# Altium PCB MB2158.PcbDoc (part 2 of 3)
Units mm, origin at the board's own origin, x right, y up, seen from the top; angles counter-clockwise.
Board outline 43 x 60 mm, 4 copper layers (Top Layer, Signal Layer 1, Signal Layer 2, Bottom Layer), stack 1.539 mm thick; 118 components, 89 nets, 427 pads, 825 vias.

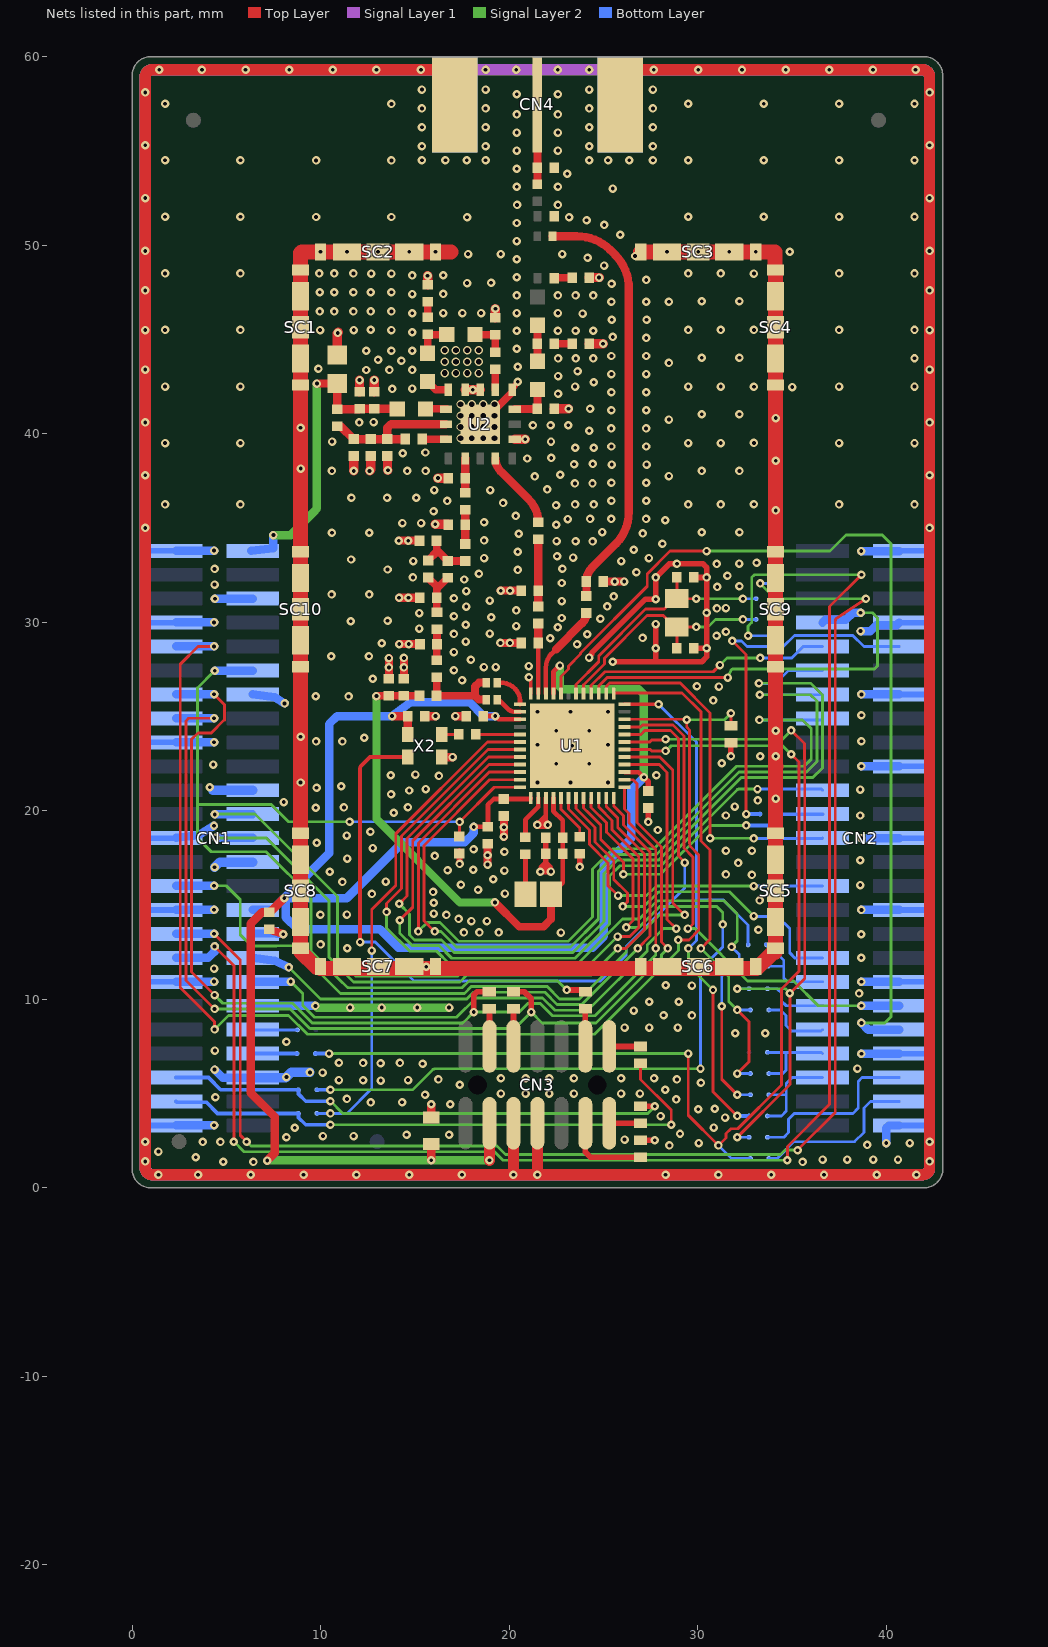
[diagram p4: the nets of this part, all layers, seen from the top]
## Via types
v1: diameter 0.45, hole 0.2, Top Layer to Bottom Layer, tented both sides, 797 vias
v2: diameter 0.45, hole 0.3, Top Layer to Bottom Layer, tented both sides, 28 vias

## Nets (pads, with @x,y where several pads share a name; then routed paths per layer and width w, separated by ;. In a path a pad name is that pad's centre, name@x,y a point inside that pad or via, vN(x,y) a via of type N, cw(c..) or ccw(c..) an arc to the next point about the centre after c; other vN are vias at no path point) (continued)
GND: C1.1 C2.1 C4.1 C7.1 C8.1 C9.1 C10.1 C11.1 C12.1 C13.1 C14.2 C15.1 C16.1 C17.1 C18.1 C19.1 C20.1 C21.1 C22.1 C23.2 C24.1 C26.1 C27.2 C28.2 C29.2 C30.2 C31.2 C34.1 C35.1 C37.1 C39.2 C40.1 CN1.1 CN1.6 CN1.7 CN1.14 CN1.17 CN1.22 CN1.25 CN1.28 CN1.31 CN1.34 CN1.37 CN1.40 CN1.46 CN1.49 CN2.2 CN2.8 CN2.14 CN2.20 CN2.26 CN2.32 CN2.38 CN2.44 CN2.50 CN3.5 CN3.7 CN4.2 CN4.3 CN4.4 CN4.5 L3.2 L12.2 L17.2 L19.2 R2.1 R8.1 SC1.1 SC2.1 SC3.1 SC4.1 SC5.1 SC6.1 SC7.1 SC8.1 SC9.1 SC10.1 U1.24 U1.39 U1.49 U2.6 U2.9 U2.11 U2.12 U2.17 X2.2 | length 1058.1
  Top Layer w0.2: v1(21.05,27.08) 21.05,27.013 21.15,26.913 U1.24@21.15,26.225
  Top Layer w0.25: v1@21.538,19.288 v1(21.5,19.25) 21.5,19.275 21.95,19.725 ; U1.39@21.95,20.675 21.95,19.725 ; v1(22.05,19.25) 21.95,19.35 21.95,19.725
  Top Layer w0.3: v1(17.37,17.179) C20.1@17.37,17.884 ; U2.17@18.9,41.154 U2.17@19.124,41.154 ; U2.9@20.148,42.178 20.202,42.178 20.175,42.205 U2.9@20.175,42.33 v1(20.453,42.759) ; C22.1@21.941,18.572 C23.2@21.941,17.722 21.941,17.235 ; v1@22.221,16.772 21.941,16.772 ; v1(22.221,16.778) 22.192,16.807 22.192,16.913 22.187,16.918 22.187,16.989 21.941,17.235 ; v1(23.75,17.02) C21.1@23.75,17.725 ; v1(24.243,28.128) 24.243,28.168 24.375,28.301 24.375,28.366 27.234,31.225 v1(27.775,31.225) v1(27.775,32.375) 28.5,33.1 v1(28.9,33.1) 30.275,33.1 30.475,32.9 v1(30.475,32.375) ; v1(25.5,27.9) 27.7,27.9 ; R8.1@26.975,2.525 v1(27.725,2.525) ; v1(27.375,19.411) C17.1@27.375,20.15 ; v1(27.775,29.9) v1(27.775,28.625) 27.775,27.975 27.7,27.9 ; C13.1@29.8,28.625 v1(30.475,28.625) ; C9.1@29.8,32.375 v1(30.475,32.375) ; v1(31.763,22.895) R2.1@31.763,23.6 ; 21.941,16.772 21.941,17.235 ; 21.941,16.772 v1(21.662,16.772) 21.69,16.801 21.69,16.907 21.695,16.912 21.695,16.995 21.935,17.235 21.941,17.235 ; 27.7,27.9 30.214,27.9 30.475,28.161 v1(30.475,28.625) ; v1(30.475,28.625) v1(30.475,30.5) v1(30.475,32.375)
  Top Layer w0.4: U2.17@19.124,41.154 U2.9@20.148,42.178
  Top Layer w0.43: C14.2@13.625,27 v1(13.625,27.6) v1(13.625,28.1) ; v1(14.15,34.325) v1(14.649,34.325) C4.1@15.25,34.325 ; v1(14.161,31.3) v1(14.661,31.3) C8.1@15.261,31.3 ; v1(14.175,28.841) v1(14.675,28.841) C11.1@15.174,28.841 ; C15.1@14.42,27.005 v1(14.42,27.605) v1(14.42,28.105) ; v1(18.857,17.146) v1(18.857,17.646) C18.1@18.857,18.246 ; v1(19.54,28.9) v1(20.04,28.9) C12.1@20.64,28.9 ; v1(19.55,31.675) v1(20.05,31.675) C10.1@20.65,31.675 ; v1(19.725,18.625) v1(19.725,19.125) C19.1@19.725,19.725 ; L3.2@25,32.16 v1(25.6,32.16) v1(26.1,32.16)
  Top Layer w0.45: C24.1@7.286,13.715 7.341,13.685 v1(8.021,13.455) ; C7.1@15.527,25.025 v1(16.102,25.025) ; C26.1@15.875,3.725 v1(15.875,4.43) ; X2.2@16.427,22.85 v1(17.002,22.85) ; v1(17.15,25.025) C16.1@17.725,25.025 ; v1(21.5,19.25) v1(22.05,19.25)
  Top Layer w0.5: C27.2@10.881,44.175 10.881,45.316 v1@10.944,45.379 ; v1(11.759,38.027) 11.77,38.038 C39.2@11.77,38.817 ; v1(12.066,42.847) 12.066,42.219 C31.2@12.068,42.217 ; v1(12.6,38.027) 12.659,38.086 C28.2@12.659,38.817 ; v1(12.842,42.847) 12.842,42.22 C29.2@12.844,42.217 ; C30.2@13.548,38.817 13.548,38.091 v1(13.572,38.066) ; v1(15.671,48.38) 15.671,48.377 15.675,48.373 L12.2@15.675,47.9 ; v1(16.079,35.192) 16.77,35.192 16.775,35.187 C40.1@16.775,35.173 ; v1(16.224,37.643) C37.1@16.775,37.643 ; U2.12@17.675,42.33 U2.11@18.475,42.33 ; v1(19.273,46.63) 19.273,46.152 C34.1@19.275,46.15 ; U2.6@20.3,39.705 v1(20.85,39.705) ; C35.1@22.4,41.322 v1(23.15,41.322) ; L17.2@24.25,44.768 v1(24.983,44.768) ; L19.2@24.25,48.282 v1(24.771,48.282)
  Top Layer w0.6: CN4.3@17.119,57.46 17.119,58.394 16.212,59.3 1.075,59.3 ccw(c1.075,58.925) 0.7,58.925 v1(0.7,43.4) v1(0.7,40.6) v1(0.7,37.8) v1(0.7,35) v1(0.7,2.45) 0.7,1.075 ccw(c1.075,1.075) 1.075,0.7 41.925,0.7 ; v1(20.225,0.7) 20.23,0.705 CN3.5@20.23,3.43 ; v1(21.5,0.7) CN3.7@21.5,3.43 ; CN4.2@25.881,57.46 25.881,58.394 26.787,59.3 41.925,59.3 cw(c41.925,58.925) 42.3,58.925 v1(42.3,35) v1(42.3,2.45) 42.3,1.075 ; 41.925,0.7 ccw(c41.925,1.075) 42.3,1.075 ; 41.925,0.7 ccw(c41.925,1.075) 42.3,1.075
  Top Layer w0.8: SC1.1@8.939,48.686 8.939,49.582 9.002,49.645 v1(9.998,49.645) v1(11.398,49.645) v1(13.048,49.645) v1(14.698,49.645) v1(16.098,49.645) 16.921,49.645 ; SC8.1@8.989,14.353 8.989,14.038 SC8.1@8.939,13.988 ; SC8.1@8.989,15.588 SC8.1@8.939,15.638 ; SC1.1@8.989,48.619 8.939,48.569 SC1.1@8.939,47.286 SC1.1@8.939,45.636 SC1.1@8.939,43.986 SC1.1@8.939,42.586 8.939,42.469 8.939,33.629 8.939,24.644 8.939,19.488 8.939,18.688 SC8.1@8.939,15.638 ; SC3.1@26.979,49.645 v1(28.379,49.645) v1(30.029,49.645) v1(31.679,49.645) v1(33.079,49.645) 34.111,49.645 34.111,48.714 SC4.1@34.139,48.686 SC4.1@34.139,47.286 SC4.1@34.139,45.636 SC4.1@34.139,43.986 SC4.1@34.139,42.586 v1(34.139,40.826) v1(34.139,38.562) v1(34.139,35.927) SC9.1@34.139,33.745 SC9.1@34.139,32.345 SC9.1@34.139,30.695 SC9.1@34.139,29.045 SC9.1@34.139,27.645 v1(34.139,24.25) 34.139,22.341 ; 34.156,22.358 34.139,22.341 ; SC8.1@8.939,13.988 SC8.1@8.939,15.638 ; SC8.1@8.939,13.988 8.939,12.538 9.798,11.679 9.949,11.679 9.999,11.629 33.129,11.629 33.988,12.488 34.089,12.488 34.139,12.538 34.139,22.341
  Signal Layer 1 w0.6: 41.925,0.7 ccw(c41.925,1.075) 42.3,1.075 ; 41.925,0.7 ccw(c41.925,1.075) 42.3,1.075 ; 41.925,0.7 1.075,0.7 cw(c1.075,1.075) 0.7,1.075 v1(0.7,2.45) v1(0.7,35) v1(0.7,37.8) v1(0.7,40.6) v1(0.7,43.4) v1(0.7,49.697) v1(0.7,52.497) 0.7,58.925 cw(c1.075,58.925) 0.7,58.933 cw(c1.075,58.925) 1.075,59.3 v1(18.75,59.3) v1(20.375,59.3) v1(22.577,59.3) 41.925,59.3 ; 41.925,59.3 cw(c41.925,58.925) 42.3,58.925 ; 41.925,59.3 cw(c41.925,58.925) 42.3,58.925 ; 42.3,1.075 v1(42.3,2.45) v1(42.3,35) v1(42.3,45.497) cw(c42.675,45.501) 42.3,45.5 v1(42.3,47.597) v1(42.3,49.697) v1(42.3,52.497) v1(42.3,55.297) 42.3,58.697 42.3,58.925
  Signal Layer 2 w0.45: v1(9.725,9.65) 9.813,9.562 v1(11.563,9.562) v1(13.25,9.562) v1(15.125,9.562) v1(16.812,9.562)
  Signal Layer 2 w0.6: 0.7,58.697 0.7,58.925 cw(c1.075,58.925) 1.074,59.3 v1(3.704,59.3) v1(18.75,59.3) v1(20.375,59.3) v1(22.577,59.3) 41.925,59.3 cw(c41.925,58.925) 42.3,58.925 v1(42.3,55.297) v1(42.3,52.497) v1(42.3,49.697) v1(42.3,35) v1(42.3,2.45) 42.3,1.075 ; 0.7,58.811 v1(0.7,52.497) v1(0.7,49.697) v1(0.7,43.4) v1(0.7,40.6) v1(0.7,37.8) v1(0.7,35) v1(0.7,2.45) 0.7,1.075 ccw(c1.075,1.075) 1.075,0.7 41.925,0.7 ; 41.925,0.7 ccw(c41.925,1.075) 42.3,1.075 ; 41.925,0.7 ccw(c41.925,1.075) 42.3,1.075
  Bottom Layer w0.3: v1(0.7,2.45) 0.7,2.491 0.55,2.641 0.55,3.308 ; v1(0.7,35) 0.7,34.959 0.55,34.809 0.55,33.788 ; CN1.49@2.331,3.308 0.55,3.308 ; CN1.37@2.331,10.928 0.55,10.928 ; CN1.31@2.331,14.738 0.55,14.738 ; CN1.25@2.331,18.548 0.55,18.548 ; CN1.17@2.331,23.628 0.55,23.628 ; CN1.7@2.331,29.978 0.55,29.978 ; CN1.1@2.331,33.788 0.55,33.788 ; v1(4.125,21.25) 4.287,21.088 ; CN2.50@40.691,3.308 42.45,3.308 ; CN2.44@40.691,7.118 42.45,7.118 ; CN2.38@40.691,10.928 42.45,10.928 ; CN2.32@40.691,14.738 42.45,14.738 ; CN2.26@40.691,18.548 42.45,18.548 ; CN2.20@40.691,22.358 42.45,22.358 ; CN2.14@40.691,26.168 42.45,26.168 ; CN2.8@40.691,29.978 42.45,29.978 ; CN2.2@40.691,33.788 42.45,33.788 ; v1(42.3,2.45) 42.3,2.491 42.45,2.641 42.45,3.308 ; v1(42.3,35) 42.329,34.971 42.329,34.821 42.45,34.7 42.45,33.788 ; 0.55,3.308 0.55,10.928 ; 0.55,10.928 0.55,14.738 ; 0.55,14.738 0.55,18.548 ; 0.55,18.548 0.55,23.628 ; 0.55,23.628 0.55,29.978 ; 0.55,29.978 0.55,33.788 ; 42.45,3.308 42.45,7.118 ; 42.45,7.118 42.45,10.928 ; 42.45,10.928 42.45,14.738 ; 42.45,14.738 42.45,18.548 ; 42.45,18.548 42.45,22.358 ; 42.45,22.358 42.45,26.168 ; 42.45,26.168 42.45,29.978 ; 42.45,29.978 42.45,33.788
  Bottom Layer w0.45: CN1.49@2.343,3.32 v1(4.35,3.32) ; CN1.37@2.343,10.94 v1(4.35,10.94) ; CN1.31@2.343,14.75 v1(4.35,14.75) ; CN1.25@2.343,18.56 3.501,18.693 v1(4.348,19.207) ; CN1.17@2.343,23.64 v1(4.35,23.64) ; CN1.7@2.343,29.99 v1(4.35,29.99) ; CN1.1@2.343,33.8 v1(4.35,33.8) ; v1(4.375,6.275) 4.802,5.848 CN1.46@6.401,5.848 ; v1(4.394,31.248) CN1.6@6.401,31.248 ; CN1.40@6.401,9.658 9.717,9.658 v1(9.725,9.65) ; CN1.34@6.401,13.468 CN1.34@7.196,13.492 ; CN1.14@6.413,26.18 7.571,26.023 v1(8.089,25.69) ; v1(8.021,13.455) CN1.34@7.219,13.492 ; v1(38.637,29.531) 39.162,29.531 39.464,29.833 40.546,29.833 CN2.8@40.691,29.978 ; v1(38.672,33.776) CN2.2@40.679,33.776 ; v1(38.684,7.118) CN2.44@40.691,7.118 ; v1(38.684,10.928) CN2.38@40.691,10.928 ; v1(38.684,14.738) CN2.32@40.691,14.738 ; v1(38.684,18.548) CN2.26@40.691,18.548 ; v1(38.684,22.358) CN2.20@40.691,22.358 ; v1(38.684,26.168) CN2.14@40.691,26.168 ; v1(40,2.375) 40,3.163 40.145,3.308 CN2.50@40.691,3.308 ; CN1.34@7.196,13.492 cw(c7.205,13.192) CN1.34@7.219,13.492 ; CN1.34@7.196,13.492 cw(c7.205,13.192) CN1.34@7.219,13.492
  Bottom Layer w0.5: 4.287,21.088 CN1.22@6.401,21.088 ; v1(4.375,17) 4.653,17.278 CN1.28@6.401,17.278 ; CN1.46@6.401,5.848 8.16,5.848 v1(8.188,5.875) 8.438,6.125 v1(9.437,6.125)
  Bottom Layer w0.6: v1(0.7,2.45) 0.7,1.075 ccw(c1.075,1.075) 1.075,0.7 41.925,0.7 ; v1(0.7,35) v1(0.7,55.297) 0.7,58.807 ccw(c-11.706,59.044) 0.702,58.929 cw(c1.077,58.925) 1.077,59.3 v1(1.446,59.3) 16.212,59.3 17.119,58.394 CN4.4@17.119,57.46 ; CN4.5@25.881,57.46 25.881,58.394 26.787,59.3 41.925,59.3 ; v1(42.3,2.45) v1(42.3,1.4) 42.3,1.075 ; v1(42.3,35) v1(42.3,37.8) 42.3,58.886 ccw(c41.837,58.886) 42.256,59.084 ; 41.925,0.7 ccw(c41.925,1.075) 42.3,1.075 ; 41.925,0.7 ccw(c41.925,1.075) 42.3,1.075 ; 41.925,59.3 cw(c41.925,58.925) 42.237,59.134 ; 41.925,59.3 cw(c41.925,58.925) 42.237,59.134 ; 42.237,59.134 ccw(c42.596,59.243) 42.256,59.084 ; 42.237,59.134 cw(c41.925,58.925) 42.3,58.925 ccw(c41.925,58.925) 42.237,59.134 ; 42.237,59.134 ccw(c42.596,59.243) 42.256,59.084
  other v1: 1.4,0.7 3.5,0.7 6.3,0.7 9.1,0.7 11.9,0.7 14.7,0.7 17.5,0.7 28.3,0.7 31.1,0.7 33.9,0.7 36.7,0.7 39.5,0.7 41.6,0.7 4.836,1.39 6.438,1.375 35.563,1.375 0.7,1.4 36.625,1.5 37.938,1.5 39.313,1.5 40.625,1.5 3.375,1.625 1.4,1.924 28.5,2.25 39,2.275 30.063,2.375 41.25,2.375 3.75,2.438 4.687,2.438 26.125,2.562 8.188,2.688 10.125,2.75 11.75,2.75 14.563,2.812 16.812,2.812 29.063,2.875 8.625,3.187 30.85,3.2 31.45,3.725 28.033,3.806 30.025,4.175 30.903,4.202 16.875,4.438 12.657,4.529 14.325,4.538 28.86,4.688 11.397,4.719 4.426,4.811 15.539,4.937 19.562,5 20.875,5 22.125,5 23.438,5 25.937,5 26.937,5 28.275,5.201 17.379,5.465 30.175,5.573 13.193,5.69 12.256,5.707 10.97,5.717 14.639,5.717 16.25,5.75 28.9,5.75 19.562,5.813 20.875,5.813 22.125,5.813 23.438,5.813 25.937,5.813 27.688,5.813 10.106,6.115 38.475,6.325 15.412,6.585 12.256,6.626 13.179,6.613 14.211,6.626 10.97,6.634 4.395,7.28 8.188,7.75 31.995,8.205 33.58,8.205 26.125,8.5 27.438,8.5 28.937,8.5 29.696,9.144 28.19,9.15 26.614,9.401 27.438,9.875 29,9.875 38.563,10.312 29.696,10.728 28.312,10.75 4.35,11.629 15.602,11.728 38.675,12.2 11.42,12.713 9.999,12.911 38.675,13.45 22.75,13.538 17.6,13.55 18.425,13.55 19.45,13.55 33.222,13.692 18,14.15 18.825,14.15 17.32,14.262 16.675,14.475 9.991,14.482 11.4,14.493 16,14.55 16,15.125 33.285,15.244 12.722,15.588 19.778,15.61 15.968,15.696 18.355,15.808 17.446,16.079 38.625,16.062 11.16,16.229 13.454,16.248 19.155,16.364 32.875,16.6 31.5,16.625 10.489,16.772 19.752,16.828 16.734,16.851 18.098,16.877 32.149,17.236 38.625,17.375 11.409,17.465 16.054,17.608 19.752,17.826 31.5,17.875 32.875,17.875 18.116,17.957 12.773,18.022 9.798,18.3 11.391,18.687 12.646,18.888 27.88,18.981 31.5,19.75 38.625,19.75 13.879,19.895 9.749,20.162 11.24,20.175 14.633,20.188 31.964,20.226 8.05,20.464 33.189,20.55 34.139,20.65 13.735,20.88 14.708,21.075 38.625,21.125 15.578,21.15 9.784,21.225 11.1,21.305 8.939,21.5 21.5,21.5 23.25,21.5 25.25,21.5 16.275,21.85 13.72,21.884 27.812,21.884 15.03,21.921 4.307,22.45 22.5,22.5 24.25,22.5 31.274,22.52 33.314,22.895 34.139,22.895 23.35,23.45 21.5,23.5 25.25,23.5 9.759,23.675 11.161,23.675 38.687,23.688 12.316,23.876 8.939,23.924 22.5,24.25 24.25,24.25 38.687,25.063 21.5,25.25 23.25,25.25 25.25,25.25 30.823,25.85 9.749,26.077 11.488,26.068 31.131,26.587 29.963,26.599 17.502,26.923 12.773,27.006 17.075,27.457 18.666,27.625 19.285,27.625 21.042,27.678 17.973,28.015 10.561,28.195 12.561,28.195 17.075,28.417 23.604,28.832 13.25,28.88 17.696,28.974 22.187,29.148 27.077,29.166 31.004,29.286 17.075,29.377 24.148,29.365 18.967,29.397 31.5,29.5 15.234,29.662 22.577,29.728 20.376,29.796 17.696,29.867 11.6,30.05 13.556,30.075 24.841,30.182 22.785,30.225 19.054,30.27 17.075,30.316 15.234,30.486 20.376,30.623 31.019,30.734 31.5,30.75 17.721,30.832 25.204,30.84 22.785,31.121 18.973,31.149 17.075,31.276 25.551,31.371 10.581,31.473 12.581,31.473 17.725,31.651 31.035,31.876 32.213,31.905 4.375,32 22.785,32.081 17.617,32.266 14.898,32.377 31.58,32.463 18.395,32.57 26.751,32.653 20.458,32.773 13.556,32.797 4.381,32.825 22.829,32.836 31.012,33.095 32.208,33.11 33.124,33.153 14.911,33.245 25.949,33.245 11.619,33.328 18.674,33.4 27.414,33.4 23.39,33.432 22.544,33.495 20.458,33.733 26.613,33.846 28.128,34.163 24.425,34.284 22.518,34.302 23.527,34.291 18.674,34.34 20.505,34.692 27.081,34.709 10.6,34.75 12.581,34.75 24.936,34.785 30.214,34.778 32.217,34.778 22.5,35.176 14.338,35.26 15.33,35.26 18.674,35.3 28.282,35.409 23.105,35.468 24.29,35.481 25.411,35.481 27.265,35.481 20.346,35.639 15.991,35.89 22.488,36.204 1.75,36.25 5.75,36.25 23.5,36.25 24.485,36.25 29.5,36.25 31.222,36.25 32.981,36.258 37.5,36.25 41.5,36.25 19.679,36.329 16.716,36.433 25.425,36.44 27.279,36.44 11.639,36.605 13.525,36.605 15.077,36.605 16.025,37.008 19,37.008 22.023,37.044 23.489,37.362 24.422,37.363 25.425,37.4 27.279,37.4 21.359,37.736 28.479,37.75 22.712,37.82 10.6,38.027 14.6,38.027 15.568,38.027 30.214,38.028 32.217,38.028 8.954,38.147 25.439,38.361 27.293,38.361 23.445,38.383 24.435,38.397 20.96,38.684 22.231,38.717 14.359,38.967 15.56,39.002 23.51,39.25 24.49,39.249 25.425,39.32 27.279,39.32 1.75,39.5 5.75,39.5 29.5,39.5 31.222,39.5 32.981,39.513 37.5,39.5 41.5,39.5 10.611,39.581 22.221,39.581 24.251,40.158 25.411,40.28 27.265,40.28 8.939,40.317 21.261,40.454 22.196,40.454 23.131,40.454 12.05,40.6 12.808,40.615 42.3,40.6 28.479,40.75 30.214,41.028 32.217,41.028 25.425,41.24 27.279,41.24 24.29,41.322 22.594,42.122 25.425,42.2 27.279,42.2 18.075,42.33 13.799,42.371 14.857,42.393 32.981,42.485 35.013,42.47 1.75,42.5 5.75,42.5 23.5,42.5 29.5,42.5 31.222,42.5 37.5,42.5 41.5,42.5 24.49,42.731 22.594,43.057 25.425,43.16 27.279,43.16 23.63,43.306 12.42,43.378 13.648,43.379 14.857,43.379 42.3,43.4 9.884,43.442 20.456,43.545 28.479,43.75 14.286,43.874 13.048,43.92 22.594,43.992 23.529,43.992 24.464,43.992 41.5,44 30.214,44.028 32.217,44.028 25.425,44.12 27.279,44.12 12.427,44.393 13.759,44.393 14.857,44.393 20.408,44.504 27.279,45.08 25.494,45.129 10.912,45.347 14.857,45.379 20.408,45.464 22.592,45.464 23.527,45.464 24.462,45.464 0.7,45.497 1.75,45.5 5.75,45.5 9.974,45.494 11.759,45.493 13.759,45.493 29.5,45.5 31.222,45.5 32.981,45.5 37.5,45.5 41.5,45.5 12.659,45.518 25.439,46.04 27.293,46.04 23.896,46.367 14.857,46.393 16.511,46.399 17.526,46.399 18.511,46.399 20.408,46.399 22.592,46.399 9.955,46.487 10.73,46.487 11.745,46.487 12.659,46.487 13.759,46.487 25.425,47 27.279,47 28.479,47 30.214,47.028 32.217,47.028 20.408,47.334 22.592,47.334 23.527,47.334 24.462,47.334 14.857,47.407 16.511,47.413 9.955,47.502 10.73,47.502 11.745,47.502 12.659,47.502 13.759,47.502 0.7,47.597 25.431,47.956 17.767,47.985 19.042,48.002 27.279,48.155 20.408,48.294 14.857,48.393 16.511,48.399 1.75,48.5 5.75,48.5 9.923,48.498 10.73,48.5 11.745,48.5 12.683,48.493 13.759,48.493 29.5,48.5 31.222,48.5 32.981,48.493 37.5,48.5 41.5,48.5 25.033,48.915 20.408,49.254 24.162,49.335 26.679,49.424 17.824,49.529 19.55,49.529 22.814,49.529 34.886,49.645 20.408,50.214 25.897,50.55 25.039,51.071 20.408,51.174 24.109,51.326 17.767,51.485 23.178,51.478 1.75,51.5 5.75,51.5 9.759,51.493 13.759,51.493 29.5,51.5 33.5,51.5 37.5,51.5 41.5,51.5 20.422,52.134 22.592,52.134 25.5,53 20.408,53.094 22.592,53.094 23.08,53.792 20.408,54.054 1.75,54.5 5.75,54.5 9.759,54.493 13.759,54.493 15.375,54.5 16.625,54.5 17.75,54.5 18.75,54.5 24.245,54.501 25.25,54.5 26.375,54.5 27.625,54.5 29.5,54.5 33.5,54.5 37.5,54.5 41.5,54.5 20.408,55.014 22.592,55.014 15.375,55.25 18.75,55.25 24.25,55.25 27.625,55.25 20.408,55.974 22.592,55.974 15.375,56.25 18.75,56.25 24.25,56.25 27.625,56.25 20.408,56.934 22.592,56.934 15.375,57.25 18.75,57.25 24.25,57.25 27.625,57.25 1.75,57.5 13.759,57.493 29.5,57.5 33.5,57.5 37.5,57.5 41.5,57.5 20.408,58 22.592,58 0.7,58.097 42.3,58.097 15.375,58.25 18.75,58.25 24.25,58.25 27.625,58.25 6.019,59.3 8.334,59.3 10.649,59.3 12.964,59.3 15.325,59.3 24.25,59.3 27.675,59.3 30.036,59.3 32.351,59.3 34.666,59.3 36.981,59.3 39.296,59.3 41.554,59.3
  other v2: 17.425,39.755 18.025,39.755 18.625,39.755 19.225,39.755 17.425,40.355 18.025,40.355 18.625,40.355 19.225,40.355 17.425,40.955 18.025,40.955 18.625,40.955 19.225,40.955 17.425,41.555 18.025,41.555 18.625,41.555 19.225,41.555 16.581,43.218 17.181,43.218 17.781,43.218 18.381,43.218 16.581,43.818 17.181,43.818 17.781,43.818 18.381,43.818 16.581,44.418 17.181,44.418 17.781,44.418 18.381,44.418
GPIO3/BOOT0: CN1.9 R2.2 U1.10 | length 71.5
  Top Layer w0.15: v1(4.35,28.72) 3.506,28.72 2.559,27.772 2.559,10.623 2.873,10.309 4.375,8.807 v1(4.375,8.4) ; U1.10@26.125,24.85 29.403,24.85 v1(29.425,24.828) ; v1(28.975,13.15) 29.537,13.15 30.06,13.673 30.06,17.663 29.62,18.104 cw(c29.726,18.209) 29.576,18.207 29.575,18.267 cw(c29.875,18.273) 29.575,18.273 29.575,23.964 ; v1@29.431,24.828 v1(29.425,24.828) ; 29.575,24.281 29.575,23.965 ; R2.2@31.763,24.5 v1(31.763,25.175) ; v1(29.425,24.828) 29.425,24.431 29.575,24.281 29.575,23.965
  Signal Layer 2 w0.15: v1(4.375,8.4) 5.125,9.15 8.306,9.15 9.306,8.15 24.532,8.15 28.975,12.593 v1(28.975,13.15) ; v1(29.425,24.828) 31.416,24.828 v1(31.763,25.175)
  Bottom Layer w0.45: CN1.9@2.343,28.72 v1(4.35,28.72)
GPIO5/SWDIO: CN1.13 R3.2 U1.1 | length 57.3
  Top Layer w0.15: v1(4.35,26.18) 4.909,25.621 4.909,24.806 4.882,24.806 4.203,24.126 3.492,24.126 3.159,23.793 3.159,11.441 v1(4.375,10.225) ; U1.1@26.125,21.25 26.125,20.099 26.363,19.861 26.363,19.363 27.775,17.951 v1(27.775,12.699)
  Top Layer w0.3: v1(18.125,9.326) 18.125,10.225 18.3,10.4 R3.2@18.95,10.4
  Signal Layer 2 w0.15: v1(4.375,10.225) 4.81,9.79 8.515,9.79 9.555,8.75 17.549,8.75 v1(18.125,9.326) 20.534,9.326 20.984,9.776 21.648,9.776 22.299,9.125 24.552,9.125 27.775,12.348 v1(27.775,12.699)
  Bottom Layer w0.45: CN1.13@2.343,26.18 v1(4.35,26.18)
GPIO6/SWCLK: CN1.15 R4.2 U1.2 | length 58.2
  Top Layer w0.15: v1(4.35,24.91) 3,24.91 2.859,24.769 2.859,11.006 v1(4.375,9.49) ; U1.2@26.125,21.65 26.564,21.65 26.614,21.6 26.779,21.435 26.779,19.371 28.075,18.075 28.075,13.035 v1(28.41,12.7)
  Top Layer w0.3: R4.2@20.225,10.4 20.231,10.406 20.8,10.406 21.17,10.035 v1(21.17,9.326)
  Signal Layer 2 w0.15: v1(4.375,9.49) 8.391,9.49 9.387,8.494 ; 9.387,8.493 ccw(c9.493,8.6) 9.493,8.45 20.232,8.45 ccw(c20.232,8.6) 20.338,8.494 v1(21.17,9.326) 21.747,8.75 24.601,8.75 28.075,12.224 28.075,12.362 28.41,12.697 v1(28.41,12.7)
  Bottom Layer w0.45: CN1.15@2.343,24.91 v1(4.35,24.91)
GPIO11: CN1.24 U1.46 | length 38.8
  Top Layer w0.15: U1.46@24.75,20.675 24.75,20.201 25.463,19.489 25.463,18.99 26.875,17.578 26.875,13.811 26.394,13.33 v1(25.752,13.33)
  Signal Layer 2 w0.15: v1(4.382,19.806) 4.406,19.83 6.513,19.83 10.895,15.448 10.895,12.207 11.879,11.224 17.265,11.224 17.617,11.576 23.998,11.576 v1(25.752,13.33)
  Bottom Layer w0.45: v1(4.382,19.806) CN1.24@6.389,19.806
GPIO12: CN1.26 U1.47 | length 38.6
  Top Layer w0.15: U1.47@25.15,20.675 25.15,20.226 25.763,19.613 25.763,19.114 27.175,17.702 27.175,13.686 26.187,12.699 v1(25.763,12.699)
  Signal Layer 2 w0.15: v1(4.438,18.56) 7.115,18.56 10.45,15.226 10.45,12.228 11.754,10.924 17.389,10.924 17.742,11.276 24.341,11.276 v1(25.763,12.699)
  Bottom Layer w0.45: v1(4.438,18.56) CN1.26@6.413,18.56
GPIO14: CN1.29 U1.5 | length 43.6
  Top Layer w0.15: U1.5@26.125,22.85 27.988,22.85 28.675,22.163 28.675,15.11 v1(29.31,14.475)
  Signal Layer 2 w0.15: v1(4.35,16.02) 4.999,16.02 5.736,15.283 5.736,13.426 6.329,12.833 7.661,12.833 7.667,12.839 8.526,12.839 11.053,10.312 17.626,10.312 17.99,10.676 22.021,10.676 22.672,10.025 23.726,10.025 26.213,12.512 26.213,12.724 27.964,14.475 v1(29.31,14.475)
  Bottom Layer w0.45: CN1.29@2.343,16.02 v1(4.35,16.02)
GPIO15/OSC32_IN: CN1.33 SB3.2 | length 81.9
  Top Layer w0.15: v1(4.35,13.48) 4.725,13.105 5.736,12.094 5.736,2.789 v1(6.075,2.45) ; v1(35.3,2) 37.3,4 37.3,30.081 ; v1(38.921,31.248) 37.366,30.205 ; 37.3,30.081 cw(c37.45,30.081) 37.366,30.205 ; 37.3,30.081 cw(c37.45,30.081) 37.366,30.205
  Signal Layer 2 w0.15: v1(6.075,2.45) 6.31,2.215 19.354,2.215 19.804,1.765 34.398,1.765 34.633,2 v1(35.3,2) ; v1(33.314,32.056) 34.122,31.248 v1(38.921,31.248)
  Bottom Layer w0.15: v1(33.314,32.056) 34.051,32.056 34.139,31.968 34.139,31.411 ; SB3.2@34,31.25 SB3.2@34.075,31.25
  Bottom Layer w0.45: CN1.33@2.343,13.48 v1(4.35,13.48)
GPIO16/OSC32_OUT: CN1.35 SB4.2 | length 87
  Top Layer w0.15: v1(4.375,12.805) 5.4,11.78 v1(5.4,2.45) ; v1(34.757,1.465) 34.757,2.194 37,4.437 37,30.831 v1(38.687,32.518)
  Signal Layer 2 w0.15: v1(5.4,2.45) 5.935,1.915 19.229,1.915 19.679,1.465 v1(34.757,1.465) ; v1(32.673,29.287) 32.673,29.787 32.864,29.977 32.864,32.364 33.017,32.518 v1(38.687,32.518)
  Bottom Layer w0.15: v1(32.673,29.287) 33.897,29.302 ; SB4.2@34.075,30.15 34.075,29.421 34.001,29.346 ; 33.897,29.302 ccw(c33.894,29.452) 34.001,29.346 ; 33.897,29.302 ccw(c33.894,29.452) 34.001,29.346
  Bottom Layer w0.45: CN1.35@2.343,12.21 4.052,12.21 4.375,12.533 v1(4.375,12.805)
GPIO17: CN1.36 U1.48 | length 31.9
  Top Layer w0.15: U1.48@25.55,20.675 25.55,20.25 26.063,19.737 26.063,19.239 27.475,17.826 27.475,13.35 v1(26.825,12.7)
  Signal Layer 2 w0.15: v1(8.306,11.693) 8.319,11.693 9.999,10.013 10.666,10.013 17.751,10.013 18.114,10.376 21.896,10.376 22.548,9.725 23.85,9.725 26.513,12.388 v1(26.825,12.7)
  Bottom Layer w0.45: CN1.36@6.413,12.21 7.571,12.053 v1(8.306,11.693)
GPIO18: CN1.38 U1.4 | length 37.2
  Top Layer w0.15: U1.4@26.125,22.45 27.964,22.45 28.375,22.039 28.375,14.235 v1(28.86,13.75)
  Signal Layer 2 w0.15: v1(8.42,10.94) 9.051,10.309 9.051,9.678 9.679,9.05 17.212,9.05 18.239,10.076 21.772,10.076 22.423,9.425 24.186,9.425 27.325,12.564 27.325,12.885 28.19,13.75 v1(28.86,13.75)
  Bottom Layer w0.45: CN1.38@6.413,10.94 v1(8.42,10.94)
GPIO21: CN1.42 SB20.2 | length 2.4
  Bottom Layer w0.15: CN1.42@6.401,8.388 6.409,8.38 SB20.2@8.774,8.38
GPIO22: CN1.44 SB12.2 | length 2.4
  Bottom Layer w0.2: CN1.44@6.401,7.118 6.408,7.125 SB12.2@8.75,7.125
GPIO23/VCP1_RX: CN1.45 R7.1 SB14.1 | length 27.2
  Top Layer w0.3: R7.1@26.975,4.325 v1(27.725,4.325)
  Signal Layer 2 w0.15: v1(10.525,4.6) 11.175,3.95 27.35,3.95 v1(27.725,4.325)
  Bottom Layer w0.2: CN1.45@2.331,5.848 4.052,5.848 4.7,5.2 SB14.1@8.825,5.2 8.835,5.19 8.835,4.974 9.211,4.598 10.523,4.598 v1(10.525,4.6)
GPIO24/VCP1_TX: CN1.47 R6.2 SB16.1 | length 30.8
  Top Layer w0.15: R6.2@26.975,6.6 26.975,5.75 28.6,4.125 v1(28.6,3.35)
  Signal Layer 2 w0.15: v1(10.525,3.35) v1(28.6,3.35)
  Bottom Layer w0.2: CN1.47@2.331,4.578 2.371,4.538 3.946,4.538 4.534,3.95 SB16.1@8.825,3.95 8.835,3.94 8.835,3.724 9.211,3.348 10.523,3.348 v1(10.525,3.35)
GPIO28: CN2.7 U1.15 | length 21.7
  Top Layer w0.15: U1.15@24.75,26.225 24.75,26.624 25.201,27.075 31.59,27.075 v1(31.597,27.068)
  Signal Layer 2 w0.15: v1(31.597,27.068) 31.751,27.427 ; v1(38.637,30.5) 39.277,30.5 39.545,30.232 39.545,27.692 39.371,27.518 31.889,27.518 ; 31.751,27.427 cw(c31.889,27.368) 31.889,27.518 ; 31.751,27.427 cw(c31.889,27.368) 31.889,27.518
  Bottom Layer w0.45: CN2.7@36.621,29.978 36.766,30.123 37.848,30.123 38.225,30.5 v1(38.637,30.5)
GPIO29: CN2.9 U1.16 | length 13.5
  Top Layer w0.15: U1.16@24.35,26.225 24.35,26.649 25.076,27.375 30.823,27.375 v1(31.178,27.73)
  Signal Layer 2 w0.15: v1(31.178,27.73) 31.556,28.108 32.184,28.108 v1(33.314,28.105)
  Bottom Layer w0.15: v1(33.314,28.105) 34.993,28.105 35.596,28.708 CN2.9@36.621,28.708
GPIO30: CN2.10 SB5.1 | length 19.7
  Top Layer w0.15: v1(31.84,29.005) 32.563,28.282 32.563,19.837 v1(32.575,19.825)
  Bottom Layer w0.15: v1(31.84,29.005) 32.318,29.005 32.614,28.709 34.539,28.709 35.133,29.303 38.229,29.303 38.824,28.708 CN2.10@40.691,28.708
  Bottom Layer w0.2: v1(32.575,19.825) SB5.1@33.3,19.825
GPIO31: CN2.11 U1.32 | length 52.3
  Top Layer w0.15: v1(14.17,15.071) 14.585,15.486 14.585,18.535 18.9,22.85 U1.32@20.575,22.85
  Signal Layer 2 w0.15: v1(14.17,15.071) 14.713,14.527 14.713,13.426 14.829,13.31 ; 14.829,13.309 14.988,13.15 15.366,13.15 16.41,13.15 17.084,12.476 23.378,12.476 25.027,14.126 25.027,16.661 25.752,17.386 27.936,17.386 32.308,21.758 36.102,21.758 36.621,22.277 36.621,26.139 35.992,26.768 v1(33.25,26.768)
  Bottom Layer w0.15: v1(33.25,26.768) 33.268,26.75 34.139,26.75 34.827,27.438 CN2.11@36.621,27.438
GPIO33: CN2.13 U1.35 | length 47.2
  Top Layer w0.15: v1(16.05,13.6) 15.485,14.165 15.485,18.162 18.973,21.65 U1.35@20.575,21.65
  Signal Layer 2 w0.15: v1(16.05,13.6) 16.39,13.601 17.215,12.776 23.253,12.776 24.727,14.25 24.727,16.785 25.628,17.686 27.812,17.686 32.184,22.058 35.767,22.058 36.321,22.612 36.321,25.826 35.997,26.15 v1(33.287,26.15)
  Bottom Layer w0.15: v1(33.287,26.15) 36.603,26.15 CN2.13@36.621,26.168
GPIO34: CN2.15 U1.34 | length 46.5
  Top Layer w0.15: v1@15.175,13.625 15.185,13.635 15.185,18.287 18.949,22.05 U1.34@20.575,22.05
  Signal Layer 2 w0.15: v1(15.175,13.6) 15.658,14.082 16.332,14.082 17.339,13.076 23.129,13.076 24.427,14.374 24.427,16.909 25.11,17.592 25.504,17.986 27.688,17.986 32.06,22.358 35.643,22.358 36.021,22.736 36.021,24.359 35.561,24.819 v1(33.279,24.819)
  Bottom Layer w0.15: v1(33.279,24.819) 36.542,24.819 CN2.15@36.621,24.898
GPIO37: CN2.21 U1.33 | length 40.9
  Top Layer w0.15: v1(14.195,14.196) 14.885,14.886 14.885,18.411 18.924,22.45 U1.33@20.575,22.45
  Signal Layer 2 w0.15: v1(14.195,14.196) 14.195,13.518 14.863,12.85 16.286,12.85 16.96,12.176 23.502,12.176 25.327,14.001 25.327,16.536 25.877,17.086 28.06,17.086 32.078,21.103 ; v1(33.173,21.15) 32.183,21.147 ; 32.078,21.103 cw(c32.184,20.997) 32.183,21.147 ; 32.078,21.103 cw(c32.184,20.997) 32.183,21.147
  Bottom Layer w0.15: v1(33.173,21.15) 36.559,21.15 CN2.21@36.621,21.088
GPIO39: CN2.23 SB5.2 U1.44 | length 16.9
  Top Layer w0.15: U1.44@23.95,20.675 23.95,20.15 24.26,19.84 24.263,19.84 24.7,19.403 24.7,19.4 24.863,19.237 24.863,18.471 26.063,17.271 v1(26.063,16.636)
  Signal Layer 2 w0.15: v1(26.063,16.636) 28.035,16.636 30.624,19.225 v1(32.575,19.225)
  Bottom Layer w0.2: v1(32.575,19.225) 32.577,19.223 33.889,19.223 34.265,19.599 34.265,19.815 SB5.2@34.275,19.825 ; SB5.2@34.275,19.818 CN2.23@36.621,19.818
GPIO41: CN2.25 U1.14 | length 19.2
  Top Layer w0.15: U1.14@25.15,26.225 25.15,26.599 25.326,26.775 29.08,26.775 30.66,25.195 v1(30.66,18.548)
  Signal Layer 2 w0.15: v1(30.66,18.548) v1(32.975,18.535)
  Bottom Layer w0.15: v1(32.975,18.535) 36.608,18.535 CN2.25@36.621,18.548
GPIO44: CN2.29 U1.42 | length 17.3
  Top Layer w0.15: U1.42@23.15,20.675 23.15,20.101 24.263,18.989 24.263,18.223 25.25,17.236 25.25,16.027 v1(25.777,15.5)
  Signal Layer 2 w0.15: v1(25.777,15.5) 27.292,15.5 27.756,15.964 cw(c27.862,15.858) 27.862,16.008 v1(32.975,16.008)
  Bottom Layer w0.15: v1(32.975,16.008) CN2.29@36.621,16.008
GPIO47: CN2.35 U1.43 | length 20.2
  Top Layer w0.15: U1.43@23.55,20.675 23.55,20.126 24.563,19.113 24.563,18.347 25.55,17.36 25.55,16.364 26.275,15.639 26.275,15.174 v1(26.026,14.925)
  Signal Layer 2 w0.15: v1(26.026,14.925) 27.141,14.925 27.863,15.648 ; v1(32.973,14.418) 32.973,14.421 31.686,15.708 31.101,15.708 31.1,15.707 28.098,15.697 ; 27.863,15.648 cw(c27.969,15.542) 27.963,15.691 ; 27.863,15.648 cw(c27.969,15.542) 27.963,15.691 ; 27.963,15.691 28.079,15.696 ; 28.079,15.696 cw(c28.099,15.247) 28.098,15.697 ; 28.079,15.696 cw(c28.099,15.247) 28.098,15.697
  Bottom Layer w0.15: v1(32.973,14.418) 32.998,14.394 34.239,14.394 34.884,13.749 34.884,12.467 35.152,12.198 CN2.35@36.621,12.198
GPIO49: CN2.37 SB6.2 SB7.1 | length 5.2
  Bottom Layer w0.15: SB7.1@33.589,12.951 SB7.1@33.652,12.888 ; SB6.2@33.727,11.752 34.569,11.752 ; SB7.1@33.737,12.885 34.569,12.053 34.569,11.752 ; CN2.37@36.621,10.928 34.757,10.928 34.569,11.115 34.569,11.752
GPIO50: CN2.39 SB8.1 | length 3.5
  Bottom Layer w0.15: SB8.1@33.7,10.562 34.21,10.562 34.275,10.498 34.439,10.334 34.439,9.918 34.699,9.658 CN2.39@36.621,9.658
GPIO51: CN2.40 U1.9 | length 26.9
  Top Layer w0.15: U1.9@26.125,24.45 26.968,24.45 27.068,24.55 28.689,24.55 29.275,23.964 29.275,18.024 29.76,17.539 29.76,13.987 29.523,13.75 v1(29.485,13.75)
  Signal Layer 2 w0.15: v1(29.485,13.75) 29.873,13.75 32.647,10.976 35.074,10.976 36.392,9.658 v1(38.684,9.658)
  Bottom Layer w0.45: v1(38.684,9.658) CN2.40@40.691,9.658
GPIO52: CN2.41 SB9.2 | length 3.7
  Bottom Layer w0.15: SB9.2@33.775,9.438 34.394,9.438 34.687,9.144 34.687,8.607 34.982,8.312 36.545,8.312 CN2.41@36.621,8.388
GPIO53: CN2.42 U1.20 | length 51.1
  Top Layer w0.15: U1.20@22.75,26.225 22.75,27.121 23.142,27.513 23.142,27.663 23.793,28.314 23.793,28.372 27.325,31.905 27.325,32.561 28.539,33.775 v1(30.475,33.775)
  Signal Layer 2 w0.15: v1(30.475,33.775) 37.015,33.775 37.864,34.623 39.79,34.623 40.25,34.163 40.25,9.075 39.925,8.75 v1(38.687,8.75)
  Bottom Layer w0.45: v1(38.687,8.75) 39.049,8.388 CN2.42@40.691,8.388
GPIO54: CN2.43 SB11.1 SB13.2 | length 4.9
  Bottom Layer w0.15: SB11.1@33.7,7.187 34.7,7.187 ; SB13.2@33.775,6.063 34.512,6.063 34.687,6.238 34.687,7.175 34.7,7.187 ; CN2.43@36.621,7.118 36.551,7.187 34.7,7.187
GPIO55: CN2.45 SB15.2 SB17.1 | length 5.5
  Bottom Layer w0.15: SB17.1@33.7,3.812 34.439,3.812 34.7,4.073 34.7,4.95 ; SB15.2@33.775,4.937 34.687,4.937 34.7,4.95 ; CN2.45@36.621,5.848 35.018,5.848 34.7,5.53 34.7,4.95
GPIO56: CN2.46 SB18.1 | length 9.5
  Bottom Layer w0.15: SB18.1@33.7,2.688 34.569,2.688 34.813,2.931 34.813,3.638 35.125,3.95 38.237,3.95 38.517,4.23 38.517,5.642 38.723,5.848 CN2.46@40.691,5.848
GPIO57: CN2.48 SB19.2 | length 8.9
  Bottom Layer w0.15: SB19.2@33.775,1.562 34.218,1.562 35.106,2.45 38.325,2.45 38.817,2.942 38.817,4.233 39.162,4.578 CN2.48@40.691,4.578
NetC1_2: C1.2 CN4.1 L1.2 | length 4
  Top Layer w0.44: 21.5,53.48 C1.2@21.5,54.1 CN4.1@21.5,57.46
NetC3_1: C3.1 U1.29 | length 2.3
  Top Layer w0.15: C3.1@18.237,24.05 U1.29@20.575,24.05
NetC3_2: C3.2 X2.3 | length 0.9
  Top Layer w0.15: X2.3@16.427,24.05 C3.2@17.338,24.05
NetC4_2: C4.2 C5.2 C6.2 L2.2 | length 2.9
  Top Layer w0.41: C6.2@15.675,33.25 15.7,33.25 15.739,33.29 15.739,33.315 16.15,33.725 ; C4.2@16.15,34.325 16.154,34.32 16.154,33.845 16.212,33.787 L2.2@16.725,33.275 ; L2.2@16.736,33.25 C5.2@17.675,33.25
NetC6_1: C6.1 C8.2 L2.1 L5.2 | length 2.8
  Top Layer w0.41: C6.1@15.686,32.375 C6.1@15.711,32.375 15.751,32.335 15.751,32.31 16.161,31.9 C8.2@16.161,31.3 16.168,31.293 16.168,30.532 L5.2@16.175,30.525 ; 16.224,31.838 L2.1@16.736,32.35
NetC9_2: C9.2 SB3.1 U1.18 X1.2 | length 13.4
  Top Layer w0.15: U1.18@23.55,26.225 23.55,26.704 24.75,27.904 24.75,28.211 27.239,30.7 28.225,30.7 28.775,31.25 X1.2@28.9,31.25 ; C9.2@28.9,32.375 X1.2@28.9,31.25 ; v1@30.075,31.25 X1.2@28.9,31.25
  Signal Layer 2 w0.15: v1(29.925,31.25) v1(32.4,31.25)
  Bottom Layer w0.15: v1(32.4,31.25) SB3.1@33.1,31.25
NetC11_2: C11.2 L5.1 L7.2 | length 1.7
  Top Layer w0.41: L7.2@16.161,27.975 16.168,27.982 16.168,28.834 C11.2@16.175,28.841 L5.1@16.175,29.625
NetC12_2: C12.2 L6.1 U1.23 | length 3.4
  Top Layer w0.25: U1.23@21.55,26.225 C12.2@21.55,28.625
  Top Layer w0.44: C12.2@21.55,28.9 L6.1@21.55,29.934
NetC13_2: C13.2 SB4.1 U1.17 X1.1 | length 12.7
  Top Layer w0.15: U1.17@23.95,26.225 23.95,26.68 25.05,27.78 25.05,28.086 27.314,30.35 28.175,30.35 28.775,29.75 X1.1@28.9,29.75 ; C13.2@28.9,28.625 X1.1@28.9,29.75 ; v1(29.925,29.75) X1.1@28.9,29.75
  Signal Layer 2 w0.15: v1@30.075,29.75 30.547,29.75 30.947,30.15 v1(32.4,30.15)
  Bottom Layer w0.15: v1(32.4,30.15) SB4.1@33.1,30.15
NetC21_2: C21.2 U1.41 | length 2.5
  Top Layer w0.15: U1.41@22.75,20.675 22.75,20.077 23.75,19.077 C21.2@23.75,18.625
NetC25_2: C25.2 U2.4 | length 5
  Top Layer w0.44: C25.2@21.55,35.3 ccw(c19.857,35.3) 21.054,36.497 19.56,37.991 ; 19.56,37.991 cw(c20.25,38.68) U2.4@19.275,38.68 ccw(c20.25,38.68) 19.56,37.991
NetC28_1: C28.1 C30.1 C39.1 L14.2 L20.1 U2.15 | length 7.7
  Top Layer w0.45: L20.1@10.881,40.392 10.911,40.362 11.1,40.362 11.745,39.717 C39.1@11.77,39.717 C28.1@12.659,39.717 C30.1@13.548,39.717 ; L14.2@14.495,39.717 C30.1@13.548,39.717 ; U2.15@16.65,40.505 13.735,40.505 13.548,40.317 C30.1@13.548,39.717
NetC32_1: C32.1 L12.1 | length 0.8
  Top Layer w0.4: C32.1@15.675,46.168 L12.1@15.675,47
NetC32_2: C32.2 L11.2 L13.1 | length 2
  Top Layer w0.4: L11.2@15.675,44.268 C32.2@15.675,45.268 ; C32.2@15.675,45.268 15.684,45.259 16.684,45.259 L13.1@16.693,45.25
NetC33_2: C33.2 C34.2 L13.2 | length 1.9
  Top Layer w0.4: L13.2@18.325,45.25 C34.2@19.275,45.25 C33.2@19.275,44.325
NetC35_2: C35.2 L16.1 U2.8 | length 2.2
  Top Layer w0.44: U2.8@20.3,41.305 20.305,41.31 21.488,41.31 C35.2@21.5,41.322 ; C35.2@21.5,41.322 L16.1@21.5,42.342
NetC36_1: C36.1 L17.1 | length 0.9
  Top Layer w0.4: C36.1@22.476,44.768 L17.1@23.35,44.768
NetC36_2: C36.2 L16.2 L18.1 | length 1.9
  Top Layer w0.44: L16.2@21.5,43.842 C36.2@21.5,44.768 L18.1@21.5,45.752
NetC37_2: C37.2 L21.2 U2.2 | length 1.8
  Top Layer w0.44: L21.2@17.675,36.86 C37.2@17.675,37.643 U2.2@17.675,38.68
NetC38_1: C38.1 L19.1 | length 0.9
  Top Layer w0.4: C38.1@22.426,48.254 22.44,48.268 23.336,48.268 L19.1@23.35,48.282
NetCN3_4: CN3.4 R3.1 | length 2
  Top Layer w0.3: R3.1@18.95,9.5 18.96,9.49 CN3.4@18.96,7.5
NetCN3_6: CN3.6 R4.1 | length 2
  Top Layer w0.3: R4.1@20.225,9.5 20.23,9.495 CN3.6@20.23,7.5
NetCN3_11: CN3.11 R8.2 | length 4.6
  Top Layer w0.3: CN3.11@24.04,3.43 24.04,1.897 24.312,1.625 R8.2@26.975,1.625
NetCN3_12: CN3.12 R5.1 | length 2
  Top Layer w0.3: CN3.12@24.04,7.5 24.04,9.49 R5.1@24.05,9.5
NetCN3_13: CN3.13 R7.2 | length 1.7
  Top Layer w0.3: CN3.13@25.31,3.43 25.315,3.425 R7.2@26.975,3.425
NetCN3_14: CN3.14 R6.1 | length 1.7
  Top Layer w0.3: CN3.14@25.31,7.5 R6.1@26.975,7.5
NetL3_1: L3.1 L4.2 R1.2 | length 22.7
  Top Layer w0.44: R1.2@22.3,50.475 23.586,50.475 cw(c23.586,47.935) 25.382,49.731 25.606,49.507 cw(c23.81,47.711) 26.35,47.711 26.35,35.835 cw(c23.96,35.835) 25.65,34.145 24.408,32.903 ccw(c25.15,32.16) L3.1@24.1,32.16 L4.2@24.1,31.391
NetL4_1: L4.1 U1.22 | length 6.5
  Top Layer w0.25: U1.22@21.95,26.225 21.95,27.601 ; 22.5,28.575 22.25,28.325 ; 21.95,27.601 cw(c22.974,27.601) 22.25,28.325 ; 21.95,27.601 cw(c22.974,27.601) 22.25,28.325
  Top Layer w0.44: 22.5,28.575 23.877,29.952 ; 23.877,29.952 ccw(c23.338,30.491) L4.1@24.1,30.491 cw(c23.338,30.491) 23.877,29.952
NetL7_1: L7.1 L8.2 SB1.2 SB2.2 | length 4.8
  Top Layer w0.41: L7.1@16.161,27.075 16.155,27.069 16.155,26.106 L8.2@16.148,26.1 17.275,26.1 18.193,26.1 ; SB2.2@18.775,25.9 18.393,25.9 18.193,26.1 ; SB1.2@18.775,26.8 18.401,26.8 18.193,26.592 18.193,26.1
NetL9_1: L9.1 L10.2 | length 2.1
  Top Layer w0.25: L10.2@20.857,15.56 L10.2@20.866,15.569 L9.1@20.866,17.697
NetL9_2: L9.2 U1.38 | length 2.4
  Top Layer w0.25: L9.2@20.866,18.597 20.866,19.518 21.55,20.202 U1.38@21.55,20.675
NetL14_1: L14.1 U2.16 | length 1.3
  Top Layer w0.4: L14.1@15.395,39.717 U2.16@16.7,39.717
NetL15_1: L15.1 U2.14 | length 1.1
  Top Layer w0.4: L15.1@15.568,41.317 U2.14@16.7,41.317
NetSB1_1: SB1.1 U1.25 | length 3.5
  Top Layer w0.25: SB1.1@19.375,26.8 SB1.1@19.528,26.8 ; U1.25@20.575,25.65 20.575,25.841 ; SB1.1@19.528,26.8 cw(c19.528,25.69) 20.312,26.475 ; SB1.1@19.528,26.8 cw(c19.528,25.69) 20.312,26.475 ; 20.312,26.475 cw(c19.679,25.841) 20.575,25.841 ; 20.313,26.475 cw(c19.679,25.841) 20.575,25.841
NetSB2_1: SB2.1 U1.26 | length 1.4
  Top Layer w0.25: SB2.1@19.375,25.9 cw(c19.375,25.746) 19.484,25.855 19.945,25.394 ccw(c20.292,25.74) 20.292,25.25 U1.26@20.575,25.25
NetSB6_1: SB6.1 SB15.1 U1.31 | length 46.5
  Top Layer w0.15: v1(13.5,14.637) 13.5,15.087 14.285,15.872 14.285,18.659 18.876,23.25 U1.31@20.575,23.25 ; v1(31.279,9.633) 31.279,5.759 v1(32.1,4.937)
  Signal Layer 2 w0.15: v1(13.5,14.637) 13.5,13.789 14.739,12.55 16.161,12.55 16.835,11.876 23.626,11.876 26.011,14.261 26.901,14.261 27.823,15.183 cw(c27.929,15.077) 27.929,15.227 30.813,15.225 31.402,15.225 32.1,14.527 32.1,13.11 31.798,12.808 v1(31.798,12.776)
  Bottom Layer w0.15: v1(31.279,9.633) 31.279,11.229 31.802,11.752 32.202,11.752 ; v1(31.798,12.776) 32.202,12.371 32.202,11.771 32.733,11.771 SB6.1@32.752,11.752 ; v1(32.1,4.937) SB15.1@32.8,4.937
NetSB7_2: SB7.2 SB17.2 U1.12 | length 30.8
  Top Layer w0.15: v1(30.813,10.498) 30.813,5.1 v1(32.1,3.812)
  Top Layer w0.2: U1.12@26.125,25.65 v1(27.924,25.65)
  Signal Layer 2 w0.15: v1(29.511,12.7) 29.511,11.8 v1(30.813,10.498)
  Bottom Layer w0.15: v1@27.85,25.65 v1(27.924,25.65) 29.935,23.639 29.935,15.283 ; v1(29.511,12.7) 29.935,13.124 29.935,15.283 ; SB7.2@32.677,12.888 32.677,13.949 31.344,15.283 29.935,15.283
  Bottom Layer w0.2: v1(32.1,3.812) SB17.2@32.725,3.812
NetSB8_2: SB8.2 SB18.2 U1.7 | length 36.6
  Top Layer w0.15: U1.7@26.125,23.65 27.461,23.65 27.561,23.75 28.261,23.75 v1(28.3,23.789) ; v1(32.1,2.688) 34.889,5.476 v1(34.889,10.325) 35.676,11.112 35.676,22.694 ; v1(34.961,24.263) 35.662,23.562 35.662,22.756 ; 35.662,22.756 cw(c35.526,22.693) 35.676,22.695 ccw(c35.526,22.693) 35.662,22.756
  Signal Layer 2 w0.15: v1(28.3,23.789) 32.852,23.798 34.495,23.798 v1(34.961,24.263) ; v1(32.1,10.562) 34.652,10.562 v1(34.889,10.325)
  Bottom Layer w0.15: v1(32.1,2.688) SB18.2@32.725,2.688 ; v1(32.1,10.562) SB8.2@32.725,10.562
NetSB9_1: SB9.1 SB13.1 U1.13 | length 27.4
  Top Layer w0.15: U1.13@25.546,26.229 25.575,26.254 29.177,26.254 30.175,25.256 30.175,18.397 30.66,17.912 30.66,13.185 v1(30.175,12.7) ; v1(32.1,6.063) 32.725,6.688 32.725,8.813 v1(32.1,9.438)
  Signal Layer 2 w0.15: v1(30.175,12.7) 31.65,11.225 31.65,9.887 v1(32.1,9.438)
  Bottom Layer w0.15: v1(32.1,6.063) SB13.1@32.8,6.063 ; v1(32.1,9.438) SB9.1@32.8,9.438
NetSB12_1: SB12.1 SB19.1 U1.6 | length 59.4
  Top Layer w0.15: U1.6@26.125,23.25 27.491,23.25 27.567,23.174 v1(28.3,23.174) ; v1(29.5,7.125) 29.5,3.85 v1(31.1,2.25) 31.5,2.65 31.5,2.875 31.763,3.137 32.126,3.137 34.438,5.449 34.438,5.813 34.439,5.813 34.439,10.551 35.376,11.487 35.376,22.329 35.376,22.578 v1(34.961,22.993)
  Signal Layer 2 w0.15: v1(10.45,7.125) v1(29.5,7.125) ; v1(28.3,23.174) 28.322,23.174 28.597,23.45 34.504,23.45 v1(34.961,22.993)
  Bottom Layer w0.15: v1(31.1,2.25) 31.788,1.562 SB19.1@32.8,1.562
  Bottom Layer w0.2: SB12.1@9.725,7.125 v1(10.45,7.125)
NetSB14_2: SB14.2 U1.45 | length 43.2
  Top Layer w0.15: U1.45@24.35,20.675 24.35,20.177 25.163,19.364 25.163,18.866 26.575,17.454 26.575,14.173 v1(26.213,13.811)
  Signal Layer 2 w0.15: v1(10.525,5.2) 14.875,5.2 15.93,6.255 cw(c16.036,6.149) 16.036,6.299 v1(30.15,6.325) ; v1(26.213,13.811) 26.875,13.811 27.989,14.925 29.401,14.925 31.012,14.925 31.327,14.611 v1(31.327,13.975)
  Bottom Layer w0.15: v1(30.15,6.325) 30.15,11.599 31.327,12.776 v1(31.327,13.975)
  Bottom Layer w0.2: SB14.2@9.8,5.2 v1(10.525,5.2)
NetSB16_2: SB16.2 U1.30 | length 26.1
  Top Layer w0.15: v1(12.711,12.585) 12.711,14.76 13.985,16.034 13.985,18.784 18.852,23.65 U1.30@20.575,23.65
  Bottom Layer w0.15: SB16.2@9.8,3.95 v1(10.525,3.95) 11.4,3.95 12.711,5.261 v1(12.711,12.585)
NRST: C20.2 CN1.12 R5.2 U1.36 | length 56.2
  Top Layer w0.15: C20.2@17.371,18.633 v1(17.371,19.412) 19.209,21.25 U1.36@20.575,21.25
  Top Layer w0.3: v1(23.055,10.498) 23.952,10.498 R5.2@24.05,10.4
  Signal Layer 2 w0.15: v1(4.381,27.425) 3.477,26.521 3.477,20.325 ; v1(11.541,19.422) 8.284,19.422 7.382,20.325 3.477,20.325 ; v1(23.055,10.498) 22.577,10.976 17.866,10.976 17.502,10.613 11.504,10.613 cw(c11.504,10.763) 11.4,10.655 10.992,11.05 9.487,12.554 9.487,15.448 7.109,17.826 4.199,17.826 3.477,18.548 3.477,20.325
  Bottom Layer w0.15: v1(11.541,19.422) 11.545,19.417 17.366,19.417 v1(17.371,19.412)
  Bottom Layer w0.45: v1(4.381,27.425) 6.388,27.425 CN1.12@6.401,27.438
PA_OUT: L11.1 U2.13 | length 1.3
  Top Layer w0.4: L11.1@15.675,42.768 16.113,42.33 U2.13@16.775,42.33
"RX Path": C10.2 C25.1 L6.2 | length 3.6
  Top Layer w0.44: L6.2@21.539,30.834 21.544,30.839 21.544,31.669 C10.2@21.55,31.675 C25.1@21.55,34.4
TCXO_EN: U1.8 X2.1 | length 43.6
  Top Layer w0.15: U1.8@26.125,24.05 26.993,24.05 27.193,24.25 28.565,24.25 28.975,23.84 28.975,17.61 v1@29.31,17.275
  Top Layer w0.2: v1(12.094,13.035) 12.096,22.256 cw(c12.271,22.255) 12.147,22.379 12.618,22.85 X2.1@14.627,22.85
  Bottom Layer w0.15: v1(12.094,13.035) 12.898,13.035 14.954,10.979 24.849,10.979 26.213,12.343 26.213,12.793 29.31,15.89 v1(29.31,17.252)
"TX Path": C5.1 C40.2 L21.1 | length 1.8
  Top Layer w0.44: C5.1@17.675,34.15 C40.2@17.675,35.173 ; C40.2@17.675,35.173 L21.1@17.675,35.96
TX_IN: C33.1 U2.10 | length 1.1
  Top Layer w0.4: U2.10@19.275,42.33 C33.1@19.275,43.425
VDD: C7.2 C16.2 C17.2 C18.2 C19.2 C24.2 C26.2 CN1.32 CN3.3 U1.3 U1.21 U1.27 U1.37 X2.4 | length 113.9
  Top Layer w0.25: v1(18.125,19.146) C18.2@18.857,19.146 18.875,19.164 18.875,20.321 19.179,20.625 C19.2@19.725,20.625 21.125,20.625 21.15,20.65 U1.37@21.15,20.675 ; C16.2@18.625,25.025 v1@19.262,25.025 ; v1(19.262,25.022) 19.434,24.85 U1.27@20.575,24.85 ; U1.21@22.35,26.225 22.35,27.38 22.669,27.699 v1(22.692,27.699) ; U1.3@26.125,22.05 26.877,22.05 v1(27.152,21.775)
  Top Layer w0.3: v1(27.152,21.775) 27.375,21.552 C17.2@27.375,21.05
  Top Layer w0.45: v1(7.175,1.45) 7.557,1.832 7.557,3.78 6.3,5.037 6.3,14.02 6.895,14.615 C24.2@7.286,14.615 7.311,14.615 8.061,15.365 v1(8.07,15.365) ; v1(13.795,25.022) 14.325,25.025 cw(c14.327,24.725) 14.327,25.025 C7.2@14.627,25.025 X2.4@14.627,24.05 ; v1(15.875,1.465) C26.2@15.875,2.325
  Top Layer w0.6: v1(18.958,1.465) 18.96,1.468 CN3.3@18.96,3.43
  Signal Layer 2 w0.45: v1(7.175,1.45) 7.19,1.465 v1(15.875,1.465) v1(18.958,1.465) ; v1(22.692,27.699) 22.692,26.587 22.829,26.45 26.87,26.45 27.152,26.168 v1(27.152,21.775)
  Bottom Layer w0.45: CN1.32@6.401,14.738 7.426,14.738 7.951,15.263 7.968,15.263 v1(8.07,15.365) ; v1(18.125,19.146) 18.125,19.028 18.125,18.824 18.05,18.749 17.635,18.334 14.359,18.334 11.39,15.365 v1(8.07,15.365) ; v1(19.262,25.022) 19.259,25.025 18.625,25.025 17.889,25.761 14.888,25.761 ; v1(27.152,21.775) 26.469,21.092 26.469,18.538 25.027,17.097 25.027,13.336 24.427,12.736 14.128,12.736 13.141,13.724 8.771,13.724 8.141,14.353 8.141,15.251 8.07,15.322 v1(8.07,15.365) ; v1(8.07,15.365) 10.45,17.745 10.45,24.594 10.881,25.024 v1(13.795,25.022) 14.708,25.701 ; 14.708,25.702 cw(c14.888,25.461) 14.888,25.761 ; 14.708,25.702 cw(c14.888,25.461) 14.888,25.761
VDD_FEM: C27.1 C29.1 C31.1 CN1.2 L15.2 L20.2 | length 17
  Top Layer w0.43: v1(9.809,42.657) C27.1@10.881,42.657
  Top Layer w0.45: C27.1@10.881,42.657 L20.2@10.881,41.292 10.893,41.305 12.062,41.305 12.075,41.317 C29.1@12.844,41.317 L15.2@14.068,41.317 L15.2@14.066,41.315
  Signal Layer 2 w0.45: v1(7.501,34.623) 8.417,34.623 9.721,35.927 ccw(c9.509,36.139) 9.809,36.139 v1(9.809,42.657)
  Bottom Layer w0.45: CN1.2@6.321,33.8 7.501,33.933 v1(7.501,34.623)
VFBSD: C14.1 C15.2 C22.2 C23.1 L8.1 L10.1 U1.40 | length 27.5
  Top Layer w0.25: L10.1@22.218,15.569 22.841,16.192 C23.1@22.841,17.722 C22.2@22.841,18.572 22.841,19.491 22.35,19.982 U1.40@22.35,20.675
  Top Layer w0.41: v1(12.964,26.084) 12.969,26.084 12.985,26.1 C14.1@13.625,26.1 L8.1@15.248,26.1 ; v1(19.25,15.136) 20.536,13.85 21.821,13.85 22.218,14.247 L10.1@22.218,15.569
  Signal Layer 2 w0.41: v1(12.964,26.084) 12.964,19.561 17.389,15.136 v1(19.25,15.136)
pads on no net: CART-1.1 CN1.3 CN1.4 CN1.5 CN1.8 CN1.10 CN1.11 CN1.16 CN1.18 CN1.19 CN1.20 CN1.21 CN1.23 CN1.27 CN1.30 CN1.39 CN1.41 CN1.43 CN1.48 CN1.50 CN2.1 CN2.3 CN2.4 CN2.5 CN2.6 CN2.12 CN2.16 CN2.17 CN2.18 CN2.19 CN2.22 CN2.24 CN2.27 CN2.28 CN2.30 CN2.31 CN2.33 CN2.34 CN2.36 CN2.47 CN2.49 CN3.1 CN3.2 CN3.8 CN3.9 CN3.10 CN3.NPTH1 CN3.NPTH2 MIRE-1.1 MIRE-2.1 MIRE-3.1 MIRE-4.1 MIRE-5.1 MIRE-6.1 U1.28 U2.5 U2.7

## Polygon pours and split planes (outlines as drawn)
GND on Signal Layer 1 "GND_L02_P000" (solid, remove dead copper, pour order 0): 0,60 43,60 43,0 0,0
GND on Signal Layer 2 "GND_L03_P002" (solid, remove dead copper, pour order 2): 0,60 43,60 43,0 0,0
GND on Bottom Layer "GND_L04_P003" (solid, remove dead copper, pour order 3): 0,60 43,60 43,0 0,0
GND on Top Layer "GND_L01_P001" (solid, remove dead copper, pour order 1): 0,60 43,60 43,0 0,0

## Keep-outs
Top Layer:
  region: 20.259,19.975 20.259,18.634 cw(c19.725,18.634) 19.725,18.1 cw(c19.725,18.625) 19.2,18.625 19.2,19.975 19.35,19.975
  region: 13.091,26.75 13.091,28.091 cw(c13.625,28.091) 13.625,28.625 cw(c13.625,28.1) 14.15,28.1 14.15,26.75 14,26.75
  region: 20.889,28.378 19.548,28.378 cw(c19.548,28.912) 19.014,28.912 cw(c19.539,28.912) 19.539,29.437 20.889,29.437 20.889,29.287
  region: 15.524,33.806 14.183,33.806 cw(c14.183,34.34) 13.649,34.34 cw(c14.174,34.34) 14.174,34.865 15.524,34.865 15.524,34.715
  region: 15.516,30.759 14.211,30.759 cw(c14.211,31.329) 13.641,31.329 cw(c14.166,31.33) 14.166,31.854 15.516,31.854 15.516,31.705
  region: 15.539,28.306 14.198,28.306 cw(c14.198,28.84) 13.664,28.84 cw(c14.206,28.848) 14.198,29.389 15.539,29.389 15.539,29.215
  region: 24.75,32.694 26.091,32.694 cw(c26.091,32.16) 26.625,32.16 cw(c26.1,32.16) 26.1,31.635 24.75,31.635 24.75,31.785
  region: 19.401,18.501 19.401,17.16 cw(c18.867,17.16) 18.867,16.626 cw(c18.867,17.151) 18.342,17.151 18.342,18.501 18.492,18.501
  region: 20.9,31.141 19.559,31.141 cw(c19.559,31.675) 19.025,31.675 cw(c19.55,31.675) 19.55,32.2 20.9,32.2 20.9,32.05
  region: 14.041,26.75 14.041,28.091 cw(c14.575,28.091) 14.575,28.625 cw(c14.575,28.1) 15.1,28.1 15.1,26.75 14.95,26.75
  region: 20.5,21.125 20.125,20.75 20.125,14.074 20.449,13.75 23.5,13.75 23.85,14.1 23.85,16.9 23.85,20.775 23.5,21.125
Signal Layer 1:
  region: 20.5,21.125 20.125,20.75 20.125,14.074 20.449,13.75 23.5,13.75 23.85,14.1 23.85,16.9 23.85,20.775 23.5,21.125
Signal Layer 2:
  region: 21.17,21.125 20.325,20.28 20.325,14.225 20.8,13.75 23.421,13.75 23.85,14.179 23.85,16.9 23.85,20.775 23.5,21.125
Bottom Layer:
  region: 20.5,21.125 20.125,20.75 20.125,14.074 20.449,13.75 23.5,13.75 23.85,14.1 23.85,16.9 23.85,20.775 23.5,21.125

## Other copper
Top Layer:
  region net GND: 19.799,42.909 19.975,42.655 20.586,42.586 20.765,42.943
  region net GND: 26.281,49.584 26.425,49.39 26.537,49.193 26.662,49 26.751,48.791 27.461,48.941 26.425,50.345 26.425,49.627
  pour cut-out: 21.221,29.557 21.221,30.141 21.123,30.239 20.919,30.239 20.919,29.559 20.921,29.557
  pour cut-out: 19.65,28.366 19.65,26.475 20.902,26.475 20.902,28.365 20.901,28.366
  pour cut-out: 28.5,32.938 28.588,33.025 30.193,33.025 30.309,32.909 30.309,28.089 30.313,28.085 30.29,28.062 28.128,28.062 27.924,28.266 27.924,32.362
  pour cut-out: 13.865,24.825 13.617,24.577 13.617,22.196 17.787,22.196 17.787,24.819
  pour cut-out: 23.375,17.375 23.388,17.362 23.388,13.601 23.385,13.597 24.864,13.597 25.763,12.699 26.187,12.699 26.187,16.723 25.55,17.36
  text "1" at 5.809,56.118 h1.5
Signal Layer 1:
  text "2" at 7.031,56.118 h1.5
Signal Layer 2:
  text "3" at 9.002,56.126 h1.5
Bottom Layer:
  text "4" at 10.183,56.12 h1.5
Multi-Layer:
  pour cut-out: 5.477,57.46 5.477,55.788 10.481,55.788 10.481,57.46

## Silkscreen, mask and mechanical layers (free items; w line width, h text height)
Top Overlay:
  lines w0.12: 19.75,25.975 20,26.225 20,26.546 20.354,26.9 22.527,26.9
  text "J" at 30.35,53.586 h10
  text "MB2158A" at 30.288,50.544 h2.3
  text "K" at 2.071,46.418 h8
  text "H" at 1.599,38.987 h10
  text "RX_WAKEUP" at 23.675,34.714 h1.3
  text "C" at 1.36,6.215 h8
  text "E" at 8.115,6.008 h9
  text "I" at 36.886,3.613 h10
M1-Board Shape:
  the board outline again, w0.1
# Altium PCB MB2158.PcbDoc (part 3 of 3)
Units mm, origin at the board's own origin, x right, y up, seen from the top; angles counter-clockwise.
Board outline 43 x 60 mm, 4 copper layers (Top Layer, Signal Layer 1, Signal Layer 2, Bottom Layer), stack 1.539 mm thick; 118 components, 89 nets, 427 pads, 825 vias.

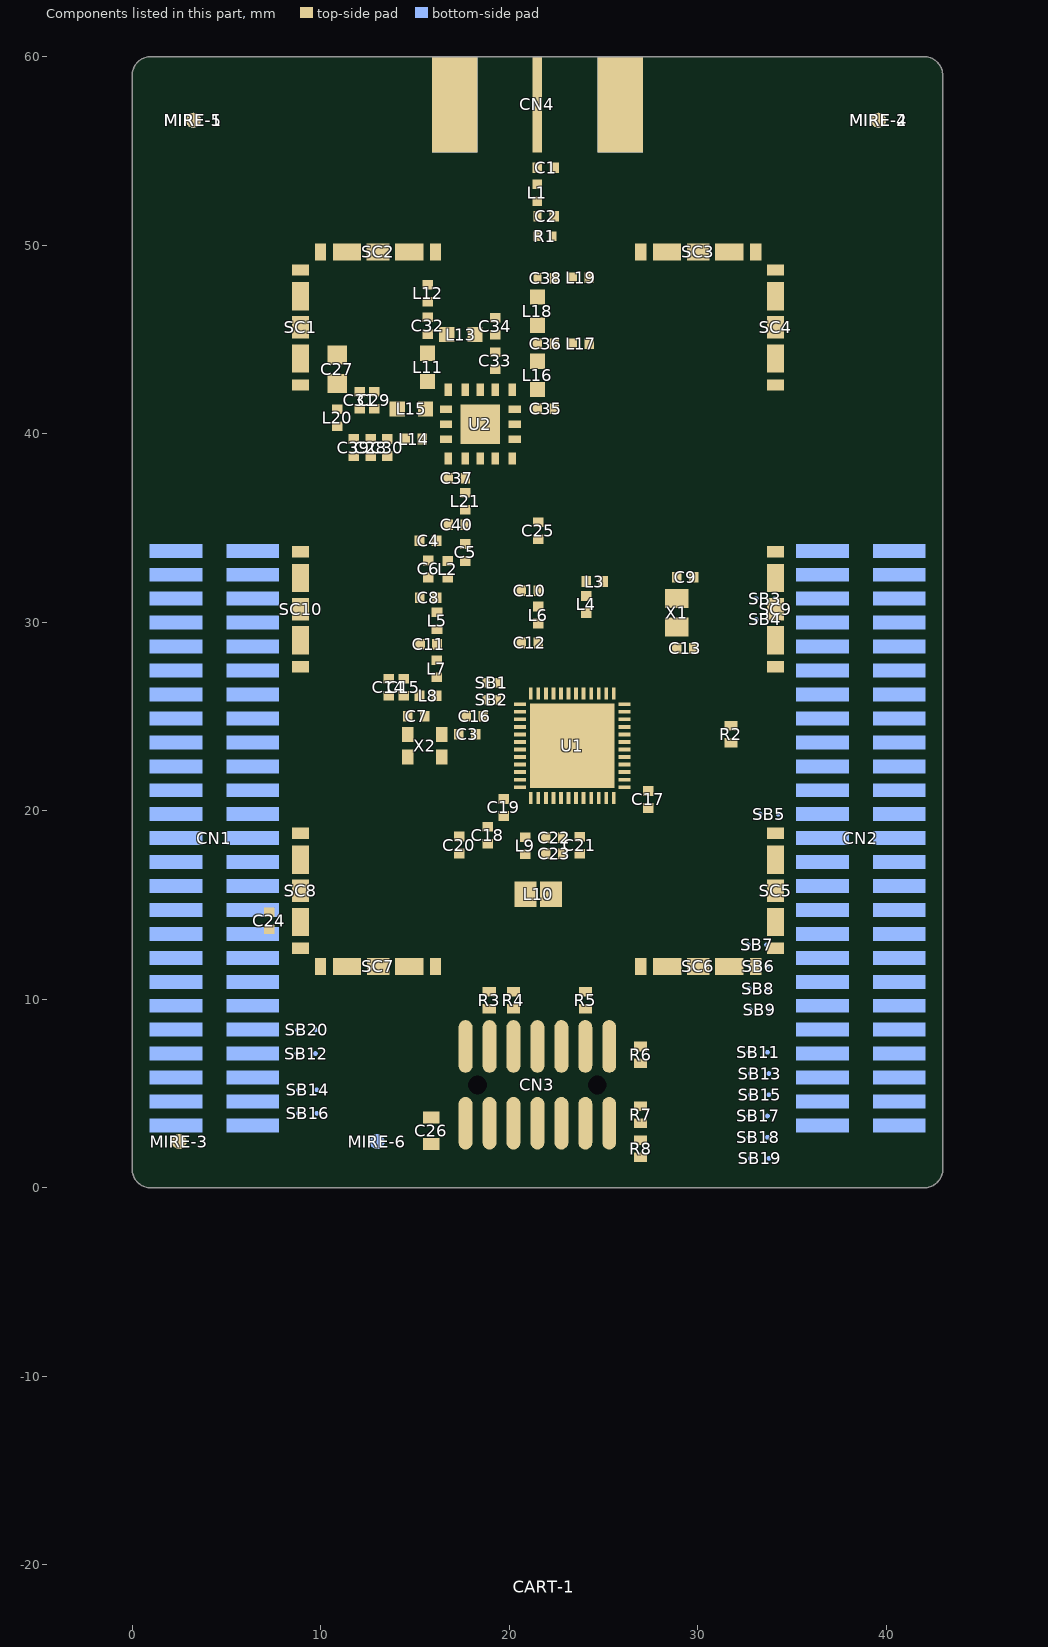
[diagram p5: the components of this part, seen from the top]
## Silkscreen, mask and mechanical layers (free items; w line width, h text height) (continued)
Drill Drawing:
  drawing of 189 lines, arcs and shapes, not listed
  text "Layer" at 107.14,109.1 h1.8
  text "Name" at 114.67,109.1 h1.8
  text "Material" at 129.227,109.1 h1.8
  text "Thickness" at 142.311,109.1 h1.8
  text "Constant" at 153.057,109.1 h1.8
  text "PCB SPECIFICATIONS :" at -42.216,108.312 h3
  text "Top Overlay" at 114.67,105.5 h1.8
  text "A.   MATERIAL :" at -42.216,104.312 h3
  text "FR-4" at -3.716,104.312 h3
  text "TG-170" at 12.784,104.312 h3
  text "X  TG-150" at 31.034,104.312 h3
  text "TG-140" at 47.034,104.312 h3
  text "Top Solder" at 114.67,101.9 h1.8
  text "Solder Resist" at 129.227,101.9 h1.8
  text "0.010mm" at 142.311,101.9 h1.8
  text "3.5" at 153.057,101.9 h1.8
  text "B.   MATERIAL FAMILY :" at -42.216,101.312 h3
  text "Ventec VT/47" at -3.716,101.312 h3
  text "C.   SOLDERMASK COLOR :" at -42.216,98.312 h3
  text "GREEN" at -3.716,98.312 h3
  text "X  BLUE" at 12.784,98.312 h3
  text "RED" at 31.034,98.312 h3
  text "BLACK" at 47.034,98.312 h3
  text "1" at 107.14,98.3 h1.8
  text "Top Layer" at 114.67,98.3 h1.8
  text "Copper" at 129.227,98.3 h1.8
  text "0.041mm" at 142.311,98.3 h1.8
  text "D.   SILKSCREEN COLOR :" at -42.216,95.312 h3
  text "X  WHITE" at -3.716,95.312 h3
  text "YELLOW" at 12.784,95.312 h3
  text "BLACK" at 31.034,95.312 h3
  text "Dielectric 1" at 114.67,94.7 h1.8
  text "FR4 VT-47" at 129.227,94.7 h1.8
  text "0.254mm" at 142.311,94.7 h1.8
  text "4" at 153.057,94.7 h1.8
  text "E.   SURFACE FINISH :" at -42.216,92.312 h3
  text "X  ENIG" at -3.716,92.312 h3
  text "IMMERSION SILVER" at 12.784,92.312 h3
  text "IMMERSION TIN" at 47.034,92.312 h3
  text "2" at 107.138,91.1 h1.8
  text "Signal Layer 1" at 114.67,91.1 h1.8
  text "Copper" at 129.227,91.1 h1.8
  text "0.018mm" at 142.311,91.1 h1.8
  text "HASL" at -3.716,89.312 h3
  text "HASL (PB-FREE)" at 12.784,89.312 h3
  text "GOLDEN FINGER" at 47.034,89.312 h3
  text "Dielectric 2" at 114.67,87.5 h1.8
  text "FR4 VT-47" at 129.227,87.5 h1.8
  text "0.914mm" at 142.311,87.5 h1.8
  text "4.3" at 153.057,87.5 h1.8
  text "F.   IMPEDANCE CONTROL :" at -42.216,86.312 h3
  text "NO" at -3.716,86.312 h3
  text "X  YES" at 12.784,86.312 h3
  text "3" at 107.14,83.9 h1.8
  text "Signal Layer 2" at 114.67,83.9 h1.8
  text "Copper" at 129.227,83.9 h1.8
  text "0.018mm" at 142.311,83.9 h1.8
  text "G.   THROUGH VIA :" at -42.216,83.312 h3
  text "PLUG THE VIAS WHICH ARE COVERED WITH SOLDERMASK ONE OR TWO SIDE." at -3.716,83.312 h3
  text "PLUG MATERIAL :" at -3.716,80.312 h3
  text "X  SOLDERMASK" at 21.784,80.312 h3
  text "NON-CONDUCTIVE EPOXY." at 47.034,80.312 h3
  text "Dielectric 3" at 114.67,80.3 h1.8
  text "FR4 VT-47" at 129.227,80.3 h1.8
  text "0.254mm" at 142.311,80.3 h1.8
  text "4" at 153.057,80.3 h1.8
  text "H.   STACK-UP :" at -42.216,77.312 h3
  text "SEE LAYER STACK-UP SEQUENCE FOR OVERALL THICKNESS." at -3.716,77.312 h3
  text "4" at 107.14,76.7 h1.8
  text "Bottom Layer" at 114.67,76.7 h1.8
  text "Copper" at 129.227,76.7 h1.8
  text "0.041mm" at 142.311,76.7 h1.8
  text "Bottom Solder" at 114.67,73.1 h1.8
  text "Solder Resist" at 129.227,73.1 h1.8
  text "0.010mm" at 142.311,73.1 h1.8
  text "3.5" at 153.057,73.1 h1.8
  text "Bottom Overlay" at 114.67,69.5 h1.8
  text "PCB : TYPE 3" at 125.413,56.046 h3
  text "ASPECT-RATIO, AXE Z :" at 125.413,50.546 h3
  text "6 :1 à 8 :1 / LEVEL \"B\"" at 125.432,43.799 h3
  text "MINIMUN PARAMETERS" at 125.425,38.075 h3
  text "DEFAULT" at 125.475,32.095 h3
  text "TRACKS : 0.150mm           / GAPS : 0.150mm" at 125.475,26.345 h3
  text "Symbol" at 64.337,15.51 h2.16
  text "Count" at 72.799,15.51 h2.16
  text "Hole Size" at 81.579,15.51 h2.16
  text "Plated" at 97.129,15.51 h2.16
  text "Hole Type" at 104.557,15.51 h2.16
  text "Drill Layer Pair" at 115.372,15.51 h2.16
  text "Via/Pad" at 135.871,15.51 h2.16
  text "Hole Length" at 144.732,15.51 h2.16
  text "797" at 72.799,11.782 h1.8
  text "0.20mm (7.87mil)" at 81.579,11.782 h1.8
  text "PTH" at 97.129,11.782 h1.8
  text "Round" at 104.557,11.782 h1.8
  text "Top Layer - Bottom Layer" at 115.372,11.782 h1.8
  text "Via" at 135.871,11.782 h1.8
  text "-" at 144.732,11.782 h1.8
  text "28" at 72.799,8.054 h1.8
  text "0.30mm (11.81mil)" at 81.579,8.054 h1.8
  text "PTH" at 97.129,8.054 h1.8
  text "Round" at 104.557,8.054 h1.8
  text "Top Layer - Bottom Layer" at 115.372,8.054 h1.8
  text "Via" at 135.871,8.054 h1.8
  text "-" at 144.732,8.054 h1.8
  text "2" at 72.799,4.325 h1.8
  text "1.00mm (39.37mil)" at 81.579,4.325 h1.8
  text "NPTH" at 97.129,4.325 h1.8
  text "Round" at 104.557,4.325 h1.8
  text "Top Layer - Bottom Layer" at 115.372,4.325 h1.8
  text "Pad" at 135.871,4.325 h1.8
  text "-" at 144.732,4.325 h1.8
  text "827 Total" at 72.799,0.597 h1.8

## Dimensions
1,0 to 1,60 on M2-Board Dimensions
0,59 to 43,59 on M2-Board Dimensions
